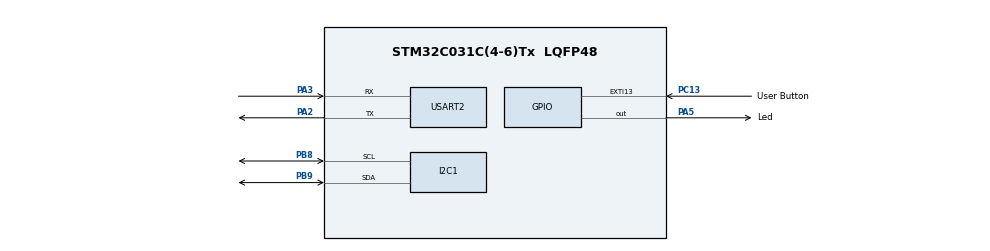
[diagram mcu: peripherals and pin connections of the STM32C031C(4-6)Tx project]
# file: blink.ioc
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I2C1.Timing=0x20303E5D
Mcu.Family=STM32C0
Mcu.Name=STM32C031C(4-6)Tx
Mcu.Package=LQFP48
NVIC.EXTI4_15_IRQn=true\:0\:0\:false\:false\:true\:true\:true\:true
PA13.Mode=Serial_Wire
PA13.Signal=DEBUG_SWDIO
PA14-BOOT0.Mode=Serial_Wire
PA14-BOOT0.Signal=DEBUG_SWCLK
PA2.Mode=Asynchronous
PA2.Signal=USART2_TX
PA3.Mode=Asynchronous
PA3.Signal=USART2_RX
PA5.GPIO_Label=Led
PA5.GPIO_Speed=GPIO_SPEED_FREQ_VERY_HIGH
PA5.PinState=GPIO_PIN_SET
PA5.Signal=GPIO_Output
PB8.Mode=I2C
PB8.Signal=I2C1_SCL
PB9.Mode=I2C
PB9.Signal=I2C1_SDA
PC13.GPIO_Label=User Button
PC13.Signal=GPXTI13
PC14-OSCX_IN\ (PC14).Mode=LSE-External-Oscillator
PC14-OSCX_IN\ (PC14).Signal=RCC_OSCX_IN
PC15-OSCX_OUT\ (PC15).Mode=LSE-External-Oscillator
PC15-OSCX_OUT\ (PC15).Signal=RCC_OSCX_OUT
PF0-OSC_IN\ (PF0).Mode=HSE-External-Oscillator
PF0-OSC_IN\ (PF0).Signal=RCC_OSC_IN
PF1-OSC_OUT\ (PF1).Mode=HSE-External-Oscillator
PF1-OSC_OUT\ (PF1).Signal=RCC_OSC_OUT
ProjectManager.HeapSize=0x200
ProjectManager.StackSize=0x400
ProjectManager.TargetToolchain=Makefile
RCC.ADCFreq_Value=48000000
RCC.AHBFreq_Value=48000000
RCC.CortexFreq_Value=48000000
RCC.EXTERNAL_CLOCK_VALUE=12288000
RCC.HCLKFreq_Value=48000000
RCC.HSE_VALUE=48000000
RCC.HSISYSCLKDivider=RCC_HSI_DIV1
RCC.HSI_VALUE=48000000
RCC.SYSCLKFreq_VALUE=48000000
USART2.VirtualMode-Asynchronous=VM_ASYNC
board=NUCLEO-C031C6

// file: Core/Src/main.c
/* USER CODE BEGIN Header */
/**
  ******************************************************************************
  * @file           : main.c
  * @brief          : Main program body
  ******************************************************************************
  * @attention
  *
  * Copyright (c) 2023 STMicroelectronics.
  * All rights reserved.
  *
  * This software is licensed under terms that can be found in the LICENSE file
  * in the root directory of this software component.
  * If no LICENSE file comes with this software, it is provided AS-IS.
  *
  ******************************************************************************
  */
/* USER CODE END Header */
#include "main.h"

/* USER CODE BEGIN Includes */

#include "amv.h"

/* USER CODE END Includes */

I2C_HandleTypeDef hi2c1;

UART_HandleTypeDef huart2;

void SystemClock_Config(void);
static void MX_GPIO_Init(void);
static void MX_I2C1_Init(void);
static void MX_USART2_UART_Init(void);

int main(void)
{

  /* MCU Configuration--------------------------------------------------------*/

  /* Reset of all peripherals, Initializes the Flash interface and the Systick. */
  HAL_Init();

  /* Configure the system clock */
  SystemClock_Config();

  /* Initialize all configured peripherals */
  MX_GPIO_Init();
  MX_I2C1_Init();
  MX_USART2_UART_Init();
  /* USER CODE BEGIN 2 */

  /* Timers (servo + cronometro de 1 us), NVIC e UART em modo interrupcao.
   * Depois disso quem manda e' o FreeRTOS: amv_start() nao retorna. */
  amv_hw_init();
  amv_start();

  /* USER CODE END 2 */

  /* Infinite loop */
  while (1)
  {

    /* USER CODE BEGIN 3 */
    /* nunca chega aqui: o escalonador do FreeRTOS assumiu a CPU */
  }
  /* USER CODE END 3 */
}

void SystemClock_Config(void)
{
  RCC_OscInitTypeDef RCC_OscInitStruct = {0};
  RCC_ClkInitTypeDef RCC_ClkInitStruct = {0};

  /** Initializes the RCC Oscillators according to the specified parameters
  * in the RCC_OscInitTypeDef structure.
  */
  RCC_OscInitStruct.OscillatorType = RCC_OSCILLATORTYPE_HSI;
  RCC_OscInitStruct.HSIState = RCC_HSI_ON;
  RCC_OscInitStruct.HSIDiv = RCC_HSI_DIV1;
  RCC_OscInitStruct.HSICalibrationValue = RCC_HSICALIBRATION_DEFAULT;
  if (HAL_RCC_OscConfig(&RCC_OscInitStruct) != HAL_OK)
  {
    Error_Handler();
  }

  /** Initializes the CPU, AHB and APB buses clocks
  */
  RCC_ClkInitStruct.ClockType = RCC_CLOCKTYPE_HCLK|RCC_CLOCKTYPE_SYSCLK
                              |RCC_CLOCKTYPE_PCLK1;
  RCC_ClkInitStruct.SYSCLKSource = RCC_SYSCLKSOURCE_HSI;
  RCC_ClkInitStruct.SYSCLKDivider = RCC_SYSCLK_DIV1;
  RCC_ClkInitStruct.AHBCLKDivider = RCC_HCLK_DIV1;
  RCC_ClkInitStruct.APB1CLKDivider = RCC_APB1_DIV1;

  if (HAL_RCC_ClockConfig(&RCC_ClkInitStruct, FLASH_LATENCY_1) != HAL_OK)
  {
    Error_Handler();
  }
}

static void MX_I2C1_Init(void)
{

  hi2c1.Instance = I2C1;
  hi2c1.Init.Timing = 0x20303E5D;
  hi2c1.Init.OwnAddress1 = 0;
  hi2c1.Init.AddressingMode = I2C_ADDRESSINGMODE_7BIT;
  hi2c1.Init.DualAddressMode = I2C_DUALADDRESS_DISABLE;
  hi2c1.Init.OwnAddress2 = 0;
  hi2c1.Init.OwnAddress2Masks = I2C_OA2_NOMASK;
  hi2c1.Init.GeneralCallMode = I2C_GENERALCALL_DISABLE;
  hi2c1.Init.NoStretchMode = I2C_NOSTRETCH_DISABLE;
  if (HAL_I2C_Init(&hi2c1) != HAL_OK)
  {
    Error_Handler();
  }

  /** Configure Analogue filter
  */
  if (HAL_I2CEx_ConfigAnalogFilter(&hi2c1, I2C_ANALOGFILTER_ENABLE) != HAL_OK)
  {
    Error_Handler();
  }

  /** Configure Digital filter
  */
  if (HAL_I2CEx_ConfigDigitalFilter(&hi2c1, 0) != HAL_OK)
  {
    Error_Handler();
  }

}

static void MX_USART2_UART_Init(void)
{

  huart2.Instance = USART2;
  huart2.Init.BaudRate = 115200;
  huart2.Init.WordLength = UART_WORDLENGTH_8B;
  huart2.Init.StopBits = UART_STOPBITS_1;
  huart2.Init.Parity = UART_PARITY_NONE;
  huart2.Init.Mode = UART_MODE_TX_RX;
  huart2.Init.HwFlowCtl = UART_HWCONTROL_NONE;
  huart2.Init.OverSampling = UART_OVERSAMPLING_16;
  huart2.Init.OneBitSampling = UART_ONE_BIT_SAMPLE_DISABLE;
  huart2.Init.ClockPrescaler = UART_PRESCALER_DIV1;
  huart2.AdvancedInit.AdvFeatureInit = UART_ADVFEATURE_NO_INIT;
  if (HAL_UART_Init(&huart2) != HAL_OK)
  {
    Error_Handler();
  }

}

static void MX_GPIO_Init(void)
{
  GPIO_InitTypeDef GPIO_InitStruct = {0};

  /* GPIO Ports Clock Enable */
  __HAL_RCC_GPIOC_CLK_ENABLE();
  __HAL_RCC_GPIOF_CLK_ENABLE();
  __HAL_RCC_GPIOA_CLK_ENABLE();
  __HAL_RCC_GPIOB_CLK_ENABLE();

  /*Configure GPIO pin Output Level */
  HAL_GPIO_WritePin(GPIOA, Heartbeat_Pin|Sinal_Amarelo_Pin, GPIO_PIN_RESET);
  HAL_GPIO_WritePin(GPIOB, Sinal_Verde_Pin|Planta_DetN_Pin|Planta_DetR_Pin, GPIO_PIN_RESET);
  /* sinal nasce VERMELHO: estado seguro desde o primeiro instante */
  HAL_GPIO_WritePin(Sinal_Vermelho_GPIO_Port, Sinal_Vermelho_Pin, GPIO_PIN_SET);

  /*Configure GPIO pins : Heartbeat_Pin Sinal_Amarelo_Pin */
  GPIO_InitStruct.Pin = Heartbeat_Pin|Sinal_Amarelo_Pin;
  GPIO_InitStruct.Mode = GPIO_MODE_OUTPUT_PP;
  GPIO_InitStruct.Pull = GPIO_NOPULL;
  GPIO_InitStruct.Speed = GPIO_SPEED_FREQ_LOW;
  HAL_GPIO_Init(GPIOA, &GPIO_InitStruct);

  /*Configure GPIO pins : Sinal_Vermelho_Pin Sinal_Verde_Pin Planta_DetN_Pin Planta_DetR_Pin */
  GPIO_InitStruct.Pin = Sinal_Vermelho_Pin|Sinal_Verde_Pin|Planta_DetN_Pin|Planta_DetR_Pin;
  HAL_GPIO_Init(GPIOB, &GPIO_InitStruct);

  /*Configure GPIO pins : Det_Normal_Pin Det_Reversa_Pin (as duas bordas) */
  GPIO_InitStruct.Pin = Det_Normal_Pin|Det_Reversa_Pin;
  GPIO_InitStruct.Mode = GPIO_MODE_IT_RISING_FALLING;
  GPIO_InitStruct.Pull = GPIO_PULLDOWN;
  HAL_GPIO_Init(GPIOA, &GPIO_InitStruct);

  /*Configure GPIO pin : Btn_Comando_Pin */
  GPIO_InitStruct.Pin = Btn_Comando_Pin;
  GPIO_InitStruct.Mode = GPIO_MODE_IT_FALLING;
  GPIO_InitStruct.Pull = GPIO_PULLUP;
  HAL_GPIO_Init(Btn_Comando_GPIO_Port, &GPIO_InitStruct);

  /*Configure GPIO pin : Btn_Emergencia_Pin */
  GPIO_InitStruct.Pin = Btn_Emergencia_Pin;
  HAL_GPIO_Init(Btn_Emergencia_GPIO_Port, &GPIO_InitStruct);

  /*Configure GPIO pin : Ocupacao_Pin */
  GPIO_InitStruct.Pin = Ocupacao_Pin;
  GPIO_InitStruct.Mode = GPIO_MODE_INPUT;
  GPIO_InitStruct.Pull = GPIO_PULLUP;
  HAL_GPIO_Init(Ocupacao_GPIO_Port, &GPIO_InitStruct);

  /*Configure GPIO pins : Obstrucao_Pin Btn_Rearme_Pin */
  GPIO_InitStruct.Pin = Obstrucao_Pin|Btn_Rearme_Pin;
  HAL_GPIO_Init(GPIOB, &GPIO_InitStruct);

  /*Configure GPIO pin : Servo_Pin (TIM3_CH1) */
  GPIO_InitStruct.Pin = Servo_Pin;
  GPIO_InitStruct.Mode = GPIO_MODE_AF_PP;
  GPIO_InitStruct.Pull = GPIO_NOPULL;
  GPIO_InitStruct.Speed = GPIO_SPEED_FREQ_LOW;
  GPIO_InitStruct.Alternate = GPIO_AF1_TIM3;
  HAL_GPIO_Init(Servo_GPIO_Port, &GPIO_InitStruct);

  /* EXTI interrupt init
   * Prioridade de NVIC 1 (0 = mais alta no M0+). O port do FreeRTOS pro M0
   * mascara todas as IRQs na secao critica, entao qualquer prioridade pode
   * chamar as funcoes ...FromISR. */
  HAL_NVIC_SetPriority(EXTI0_1_IRQn, 1, 0);
  HAL_NVIC_EnableIRQ(EXTI0_1_IRQn);

  HAL_NVIC_SetPriority(EXTI4_15_IRQn, 1, 0);
  HAL_NVIC_EnableIRQ(EXTI4_15_IRQn);

}

void Error_Handler(void)
{
  /* USER CODE BEGIN Error_Handler_Debug */
  /* User can add his own implementation to report the HAL error return state */
  amv_hw_estado_seguro();
  __disable_irq();
  while (1)
  {
  }
  /* USER CODE END Error_Handler_Debug */
}
